VERSION 5.6 ;
BUSBITCHARS "[]" ;
DIVIDERCHAR "/" ;

UNITS
  DATABASE MICRONS 2000 ;
END UNITS

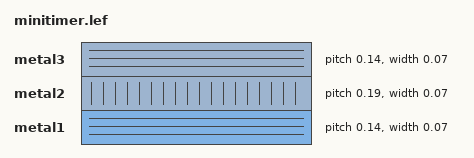
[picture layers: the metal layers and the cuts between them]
LAYER metal1
  TYPE ROUTING ;
  DIRECTION HORIZONTAL ;
  PITCH 0.14 ;
  WIDTH 0.07 ;
END metal1

LAYER metal2
  TYPE ROUTING ;
  DIRECTION VERTICAL ;
  PITCH 0.19 ;
  WIDTH 0.07 ;
END metal2

LAYER metal3
  TYPE ROUTING ;
  DIRECTION HORIZONTAL ;
  PITCH 0.14 ;
  WIDTH 0.07 ;
END metal3

SITE FreePDK45_38x28_10R_NP_162NW_34O
  SYMMETRY Y ;
  CLASS CORE ;
  SIZE 0.19 BY 1.4 ;
END FreePDK45_38x28_10R_NP_162NW_34O

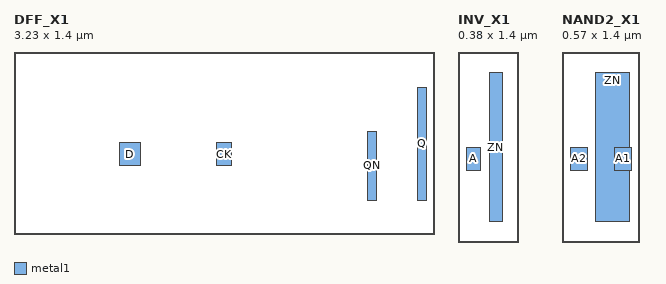
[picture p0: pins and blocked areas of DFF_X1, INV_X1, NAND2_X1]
MACRO DFF_X1
  CLASS CORE ;
  ORIGIN 0 0 ;
  FOREIGN DFF_X1 0 0 ;
  SIZE 3.23 BY 1.4 ;
  SYMMETRY X Y ;
  SITE FreePDK45_38x28_10R_NP_162NW_34O ;
  PIN D
    DIRECTION INPUT ;
    PORT
      LAYER metal1 ;
        RECT 0.81 0.53 0.97 0.70 ;
    END
  END D
  PIN CK
    DIRECTION INPUT ;
    PORT
      LAYER metal1 ;
        RECT 1.56 0.53 1.67 0.70 ;
    END
  END CK
  PIN Q
    DIRECTION OUTPUT ;
    PORT
      LAYER metal1 ;
        RECT 3.10 0.26 3.17 1.13 ;
    END
  END Q
  PIN QN
    DIRECTION OUTPUT ;
    PORT
      LAYER metal1 ;
        RECT 2.72 0.26 2.79 0.79 ;
    END
  END QN
END DFF_X1

MACRO INV_X1
  CLASS CORE ;
  ORIGIN 0 0 ;
  FOREIGN INV_X1 0 0 ;
  SIZE 0.38 BY 1.4 ;
  SYMMETRY X Y ;
  SITE FreePDK45_38x28_10R_NP_162NW_34O ;
  PIN A
    DIRECTION INPUT ;
    PORT
      LAYER metal1 ;
        RECT 0.06 0.525 0.165 0.70 ;
    END
  END A
  PIN ZN
    DIRECTION OUTPUT ;
    PORT
      LAYER metal1 ;
        RECT 0.23 0.15 0.325 1.25 ;
    END
  END ZN
END INV_X1

MACRO NAND2_X1
  CLASS CORE ;
  ORIGIN 0 0 ;
  FOREIGN NAND2_X1 0 0 ;
  SIZE 0.57 BY 1.4 ;
  SYMMETRY X Y ;
  SITE FreePDK45_38x28_10R_NP_162NW_34O ;
  PIN A1
    DIRECTION INPUT ;
    PORT
      LAYER metal1 ;
        RECT 0.385 0.525 0.51 0.70 ;
    END
  END A1
  PIN A2
    DIRECTION INPUT ;
    PORT
      LAYER metal1 ;
        RECT 0.06 0.525 0.185 0.70 ;
    END
  END A2
  PIN ZN
    DIRECTION OUTPUT ;
    PORT
      LAYER metal1 ;
        RECT 0.25 0.15 0.50 1.25 ;
    END
  END ZN
END NAND2_X1

END LIBRARY
